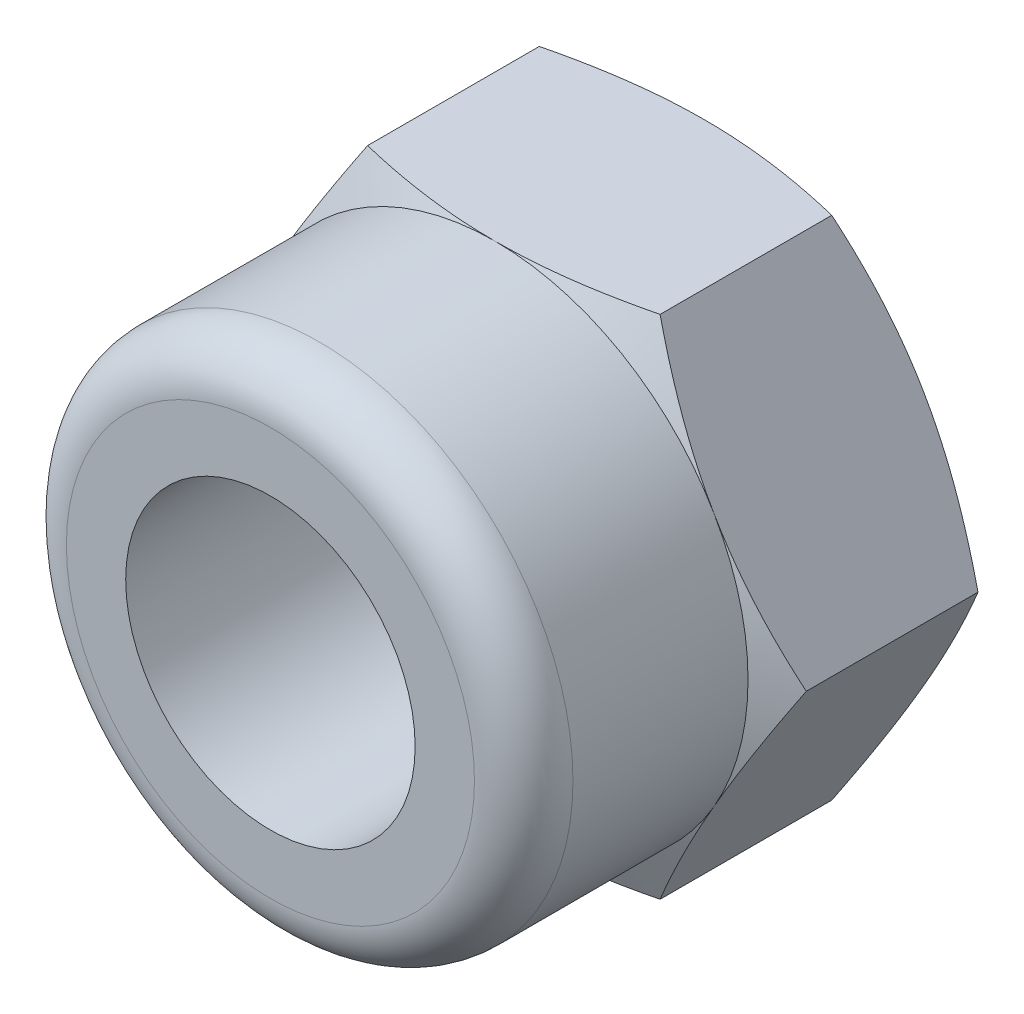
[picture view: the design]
ISO-10303-21;
HEADER;
FILE_DESCRIPTION(('STEP AP214'),'2;1');
FILE_NAME('part.step','',(''),(''),'','','');
FILE_SCHEMA(('AUTOMOTIVE_DESIGN { 1 0 10303 214 1 1 1 1 }'));
ENDSEC;
DATA;
#1=APPLICATION_CONTEXT('core data for automotive mechanical design processes');
#2=APPLICATION_PROTOCOL_DEFINITION('international standard','automotive_design',2000,#1);
#3=PRODUCT_CONTEXT('',#1,'mechanical');
#4=PRODUCT('Part','Part','',(#3));
#5=PRODUCT_RELATED_PRODUCT_CATEGORY('part','',(#4));
#6=PRODUCT_DEFINITION_FORMATION('','',#4);
#7=PRODUCT_DEFINITION_CONTEXT('part definition',#1,'design');
#8=PRODUCT_DEFINITION('design','',#6,#7);
#9=PRODUCT_DEFINITION_SHAPE('','',#8);
#10=(LENGTH_UNIT() NAMED_UNIT(*) SI_UNIT(.MILLI.,.METRE.));
#11=(NAMED_UNIT(*) PLANE_ANGLE_UNIT() SI_UNIT($,.RADIAN.));
#12=(NAMED_UNIT(*) SI_UNIT($,.STERADIAN.) SOLID_ANGLE_UNIT());
#13=UNCERTAINTY_MEASURE_WITH_UNIT(LENGTH_MEASURE(1.E-05),#10,'distance_accuracy_value','');
#14=(GEOMETRIC_REPRESENTATION_CONTEXT(3) GLOBAL_UNCERTAINTY_ASSIGNED_CONTEXT((#13)) GLOBAL_UNIT_ASSIGNED_CONTEXT((#10,
#11,#12)) REPRESENTATION_CONTEXT('',''));
#15=CARTESIAN_POINT('',(0.,0.,0.));
#16=DIRECTION('',(0.,0.,1.));
#17=DIRECTION('',(1.,0.,0.));
#18=AXIS2_PLACEMENT_3D('',#15,#16,#17);
#19=CARTESIAN_POINT('',(-4.04145188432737,0.,2.9));
#20=DIRECTION('',(0.86602540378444,-0.499999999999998,0.));
#21=DIRECTION('',(0.499999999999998,0.86602540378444,0.));
#22=AXIS2_PLACEMENT_3D('',#19,#20,#21);
#23=PLANE('',#22);
#24=CARTESIAN_POINT('',(-4.0415673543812,-0.000200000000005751,2.63630741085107));
#25=CARTESIAN_POINT('',(-3.9830643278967,0.101130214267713,2.66479349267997));
#26=CARTESIAN_POINT('',(-3.92433803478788,0.202847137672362,2.69153748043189));
#27=CARTESIAN_POINT('',(-3.80642809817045,0.407073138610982,2.74095110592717));
#28=CARTESIAN_POINT('',(-3.74724423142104,0.509582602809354,2.76361860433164));
#29=CARTESIAN_POINT('',(-3.62839363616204,0.715437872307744,2.80428400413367));
#30=CARTESIAN_POINT('',(-3.56872638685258,0.818784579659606,2.82227589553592));
#31=CARTESIAN_POINT('',(-3.44905985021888,1.02605310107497,2.85296825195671));
#32=CARTESIAN_POINT('',(-3.38906062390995,1.12997480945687,2.86566965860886));
#33=CARTESIAN_POINT('',(-3.27014272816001,1.33594664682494,2.88509966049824));
#34=CARTESIAN_POINT('',(-3.2112292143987,1.43798784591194,2.89195312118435));
#35=CARTESIAN_POINT('',(-3.09330061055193,1.64224617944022,2.89988573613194));
#36=CARTESIAN_POINT('',(-3.0342855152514,1.74446332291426,2.9009645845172));
#37=CARTESIAN_POINT('',(-2.91636155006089,1.9487136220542,2.89730537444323));
#38=CARTESIAN_POINT('',(-2.85745263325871,2.05074685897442,2.89257326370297));
#39=CARTESIAN_POINT('',(-2.73982177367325,2.25448948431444,2.8774903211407));
#40=CARTESIAN_POINT('',(-2.6810998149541,2.35619890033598,2.86713998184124));
#41=CARTESIAN_POINT('',(-2.5720716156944,2.54504128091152,2.84300281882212));
#42=CARTESIAN_POINT('',(-2.52172731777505,2.63224016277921,2.82989137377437));
#43=CARTESIAN_POINT('',(-2.42130191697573,2.80618205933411,2.80010631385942));
#44=CARTESIAN_POINT('',(-2.37122082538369,2.89292505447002,2.78343254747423));
#45=CARTESIAN_POINT('',(-2.27085880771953,3.06675716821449,2.74669891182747));
#46=CARTESIAN_POINT('',(-2.2205808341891,3.15384117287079,2.72660706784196));
#47=CARTESIAN_POINT('',(-2.12035232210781,3.32744204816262,2.6835328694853));
#48=CARTESIAN_POINT('',(-2.07040167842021,3.41395910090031,2.66055149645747));
#49=CARTESIAN_POINT('',(-2.02061047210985,3.50020000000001,2.63630741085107));
#50=B_SPLINE_CURVE_WITH_KNOTS('',3,(#24,#25,#26,#27,#28,#29,#30,#31,#32,#33,#34,#35,#36,#37,#38,
#39,#40,#41,#42,#43,#44,#45,#46,#47,#48,#49),.UNSPECIFIED.,.F.,.F.,(4,2,2,2,2,2,2,2,2,2,2,2,4),
(0.,0.361290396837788,0.722769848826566,1.08471167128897,1.44658904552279,1.80053110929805,
2.15449192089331,2.50809074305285,2.86165857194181,3.16620775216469,3.47076988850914,
3.77835581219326,4.08583755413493),.UNSPECIFIED.);
#51=CARTESIAN_POINT('',(-4.04145188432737,0.,2.63636363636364));
#52=VERTEX_POINT('',#51);
#53=CARTESIAN_POINT('',(-3.0310889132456,1.75000000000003,2.9));
#54=VERTEX_POINT('',#53);
#55=EDGE_CURVE('E142',#52,#54,#50,.T.);
#56=ORIENTED_EDGE('',*,*,#55,.T.);
#57=CARTESIAN_POINT('',(-2.02072594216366,3.5,2.63636363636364));
#58=VERTEX_POINT('',#57);
#59=EDGE_CURVE('E148',#54,#58,#50,.T.);
#60=ORIENTED_EDGE('',*,*,#59,.T.);
#61=DIRECTION('',(0.,0.,-1.));
#62=VECTOR('',#61,1.);
#63=CARTESIAN_POINT('',(-2.02072594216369,3.5,2.9));
#64=LINE('',#63,#62);
#65=CARTESIAN_POINT('',(-2.02072594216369,3.5,0.263636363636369));
#66=VERTEX_POINT('',#65);
#67=EDGE_CURVE('E232',#58,#66,#64,.T.);
#68=ORIENTED_EDGE('',*,*,#67,.T.);
#69=CARTESIAN_POINT('',(-2.02061047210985,3.50020000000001,0.263692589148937));
#70=CARTESIAN_POINT('',(-2.07911349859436,3.39886978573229,0.235206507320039));
#71=CARTESIAN_POINT('',(-2.13783979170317,3.29715286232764,0.20846251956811));
#72=CARTESIAN_POINT('',(-2.2557497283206,3.09292686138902,0.15904889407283));
#73=CARTESIAN_POINT('',(-2.31493359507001,2.99041739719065,0.136381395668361));
#74=CARTESIAN_POINT('',(-2.43378419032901,2.78456212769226,0.0957159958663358));
#75=CARTESIAN_POINT('',(-2.49345143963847,2.6812154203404,0.0777241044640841));
#76=CARTESIAN_POINT('',(-2.61311797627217,2.47394689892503,0.0470317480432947));
#77=CARTESIAN_POINT('',(-2.6731172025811,2.37002519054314,0.0343303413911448));
#78=CARTESIAN_POINT('',(-2.79203509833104,2.16405335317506,0.0149003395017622));
#79=CARTESIAN_POINT('',(-2.85094861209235,2.06201215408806,0.00804687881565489));
#80=CARTESIAN_POINT('',(-2.96887721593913,1.85775382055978,0.000114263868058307));
#81=CARTESIAN_POINT('',(-3.02789231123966,1.75553667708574,-0.000964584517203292));
#82=CARTESIAN_POINT('',(-3.14581627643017,1.5512863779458,0.00269462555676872));
#83=CARTESIAN_POINT('',(-3.20472519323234,1.44925314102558,0.00742673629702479));
#84=CARTESIAN_POINT('',(-3.3223560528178,1.24551051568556,0.0225096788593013));
#85=CARTESIAN_POINT('',(-3.38107801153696,1.14380109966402,0.0328600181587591));
#86=CARTESIAN_POINT('',(-3.49010621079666,0.954958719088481,0.0569971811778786));
#87=CARTESIAN_POINT('',(-3.540450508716,0.86775983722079,0.070108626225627));
#88=CARTESIAN_POINT('',(-3.64087590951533,0.693817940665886,0.0998936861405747));
#89=CARTESIAN_POINT('',(-3.69095700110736,0.607074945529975,0.11656745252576));
#90=CARTESIAN_POINT('',(-3.79131901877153,0.433242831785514,0.153301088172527));
#91=CARTESIAN_POINT('',(-3.84159699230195,0.346158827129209,0.17339293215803));
#92=CARTESIAN_POINT('',(-3.94182550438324,0.172557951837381,0.216467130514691));
#93=CARTESIAN_POINT('',(-3.99177614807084,0.0860408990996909,0.239448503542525));
#94=CARTESIAN_POINT('',(-4.0415673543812,-0.000200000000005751,0.263692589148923));
#95=B_SPLINE_CURVE_WITH_KNOTS('',3,(#69,#70,#71,#72,#73,#74,#75,#76,#77,#78,#79,#80,#81,#82,#83,
#84,#85,#86,#87,#88,#89,#90,#91,#92,#93,#94),.UNSPECIFIED.,.F.,.F.,(4,2,2,2,2,2,2,2,2,2,2,2,4),
(0.,0.361290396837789,0.722769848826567,1.08471167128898,1.44658904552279,1.80053110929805,
2.15449192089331,2.50809074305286,2.86165857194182,3.16620775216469,3.47076988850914,
3.77835581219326,4.08583755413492),.UNSPECIFIED.);
#96=CARTESIAN_POINT('',(-3.03108891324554,1.75,0.));
#97=VERTEX_POINT('',#96);
#98=EDGE_CURVE('E231',#66,#97,#95,.T.);
#99=ORIENTED_EDGE('',*,*,#98,.T.);
#100=CARTESIAN_POINT('',(-4.04145188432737,0.,0.263636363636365));
#101=VERTEX_POINT('',#100);
#102=EDGE_CURVE('E225',#97,#101,#95,.T.);
#103=ORIENTED_EDGE('',*,*,#102,.T.);
#104=DIRECTION('',(0.,0.,-1.));
#105=VECTOR('',#104,1.);
#106=CARTESIAN_POINT('',(-4.04145188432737,0.,2.9));
#107=LINE('',#106,#105);
#108=EDGE_CURVE('E241',#52,#101,#107,.T.);
#109=ORIENTED_EDGE('',*,*,#108,.F.);
#110=EDGE_LOOP('',(#56,#60,#68,#99,#103,#109));
#111=FACE_BOUND('',#110,.T.);
#112=ADVANCED_FACE('F31',(#111),#23,.F.);
#113=CARTESIAN_POINT('',(-2.02072594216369,-3.5,2.9));
#114=DIRECTION('',(0.86602540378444,0.499999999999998,0.));
#115=DIRECTION('',(-0.499999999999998,0.86602540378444,0.));
#116=AXIS2_PLACEMENT_3D('',#113,#114,#115);
#117=PLANE('',#116);
#118=CARTESIAN_POINT('',(-2.02061047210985,-3.50020000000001,2.63630741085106));
#119=CARTESIAN_POINT('',(-2.07911349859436,-3.39886978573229,2.66479349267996));
#120=CARTESIAN_POINT('',(-2.13783979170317,-3.29715286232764,2.69153748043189));
#121=CARTESIAN_POINT('',(-2.2557497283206,-3.09292686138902,2.74095110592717));
#122=CARTESIAN_POINT('',(-2.31493359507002,-2.99041739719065,2.76361860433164));
#123=CARTESIAN_POINT('',(-2.43378419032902,-2.78456212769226,2.80428400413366));
#124=CARTESIAN_POINT('',(-2.49345143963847,-2.6812154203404,2.82227589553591));
#125=CARTESIAN_POINT('',(-2.61311797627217,-2.47394689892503,2.8529682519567));
#126=CARTESIAN_POINT('',(-2.6731172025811,-2.37002519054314,2.86566965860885));
#127=CARTESIAN_POINT('',(-2.79203509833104,-2.16405335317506,2.88509966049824));
#128=CARTESIAN_POINT('',(-2.85094861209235,-2.06201215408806,2.89195312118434));
#129=CARTESIAN_POINT('',(-2.96887721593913,-1.85775382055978,2.89988573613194));
#130=CARTESIAN_POINT('',(-3.02789231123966,-1.75553667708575,2.9009645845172));
#131=CARTESIAN_POINT('',(-3.14581627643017,-1.5512863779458,2.89730537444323));
#132=CARTESIAN_POINT('',(-3.20472519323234,-1.44925314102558,2.89257326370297));
#133=CARTESIAN_POINT('',(-3.3223560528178,-1.24551051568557,2.8774903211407));
#134=CARTESIAN_POINT('',(-3.38107801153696,-1.14380109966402,2.86713998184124));
#135=CARTESIAN_POINT('',(-3.49010621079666,-0.954958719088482,2.84300281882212));
#136=CARTESIAN_POINT('',(-3.540450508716,-0.867759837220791,2.82989137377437));
#137=CARTESIAN_POINT('',(-3.64087590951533,-0.693817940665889,2.80010631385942));
#138=CARTESIAN_POINT('',(-3.69095700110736,-0.607074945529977,2.78343254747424));
#139=CARTESIAN_POINT('',(-3.79131901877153,-0.433242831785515,2.74669891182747));
#140=CARTESIAN_POINT('',(-3.84159699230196,-0.346158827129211,2.72660706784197));
#141=CARTESIAN_POINT('',(-3.94182550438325,-0.172557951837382,2.68353286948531));
#142=CARTESIAN_POINT('',(-3.99177614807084,-0.0860408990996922,2.66055149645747));
#143=CARTESIAN_POINT('',(-4.0415673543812,0.000200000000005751,2.63630741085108));
#144=B_SPLINE_CURVE_WITH_KNOTS('',3,(#118,#119,#120,#121,#122,#123,#124,#125,#126,#127,#128,
#129,#130,#131,#132,#133,#134,#135,#136,#137,#138,#139,#140,#141,#142,#143),.UNSPECIFIED.,.F.,
.F.,(4,2,2,2,2,2,2,2,2,2,2,2,4),(0.,0.361290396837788,0.722769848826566,1.08471167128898,
1.44658904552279,1.80053110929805,2.15449192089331,2.50809074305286,2.86165857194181,
3.16620775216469,3.47076988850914,3.77835581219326,4.08583755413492),.UNSPECIFIED.);
#145=CARTESIAN_POINT('',(-2.02072594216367,-3.5,2.63636363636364));
#146=VERTEX_POINT('',#145);
#147=CARTESIAN_POINT('',(-3.0310889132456,-1.75000000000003,2.9));
#148=VERTEX_POINT('',#147);
#149=EDGE_CURVE('E196',#146,#148,#144,.T.);
#150=ORIENTED_EDGE('',*,*,#149,.T.);
#151=EDGE_CURVE('E191',#148,#52,#144,.T.);
#152=ORIENTED_EDGE('',*,*,#151,.T.);
#153=ORIENTED_EDGE('',*,*,#108,.T.);
#154=CARTESIAN_POINT('',(-4.0415673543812,0.000200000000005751,0.26369258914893));
#155=CARTESIAN_POINT('',(-3.9830643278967,-0.101130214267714,0.235206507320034));
#156=CARTESIAN_POINT('',(-3.92433803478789,-0.202847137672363,0.208462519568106));
#157=CARTESIAN_POINT('',(-3.80642809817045,-0.407073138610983,0.159048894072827));
#158=CARTESIAN_POINT('',(-3.74724423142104,-0.509582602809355,0.136381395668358));
#159=CARTESIAN_POINT('',(-3.62839363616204,-0.715437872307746,0.0957159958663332));
#160=CARTESIAN_POINT('',(-3.56872638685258,-0.818784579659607,0.0777241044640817));
#161=CARTESIAN_POINT('',(-3.44905985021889,-1.02605310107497,0.0470317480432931));
#162=CARTESIAN_POINT('',(-3.38906062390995,-1.12997480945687,0.0343303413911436));
#163=CARTESIAN_POINT('',(-3.27014272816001,-1.33594664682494,0.014900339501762));
#164=CARTESIAN_POINT('',(-3.2112292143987,-1.43798784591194,0.00804687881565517));
#165=CARTESIAN_POINT('',(-3.09330061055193,-1.64224617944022,0.000114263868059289));
#166=CARTESIAN_POINT('',(-3.0342855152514,-1.74446332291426,-0.0009645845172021));
#167=CARTESIAN_POINT('',(-2.91636155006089,-1.94871362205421,0.00269462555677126));
#168=CARTESIAN_POINT('',(-2.85745263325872,-2.05074685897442,0.00742673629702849));
#169=CARTESIAN_POINT('',(-2.73982177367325,-2.25448948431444,0.0225096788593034));
#170=CARTESIAN_POINT('',(-2.6810998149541,-2.35619890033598,0.0328600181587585));
#171=CARTESIAN_POINT('',(-2.5720716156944,-2.54504128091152,0.0569971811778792));
#172=CARTESIAN_POINT('',(-2.52172731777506,-2.63224016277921,0.0701086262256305));
#173=CARTESIAN_POINT('',(-2.42130191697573,-2.80618205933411,0.0998936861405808));
#174=CARTESIAN_POINT('',(-2.3712208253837,-2.89292505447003,0.116567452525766));
#175=CARTESIAN_POINT('',(-2.27085880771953,-3.06675716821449,0.153301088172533));
#176=CARTESIAN_POINT('',(-2.2205808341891,-3.15384117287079,0.173392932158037));
#177=CARTESIAN_POINT('',(-2.12035232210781,-3.32744204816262,0.216467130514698));
#178=CARTESIAN_POINT('',(-2.07040167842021,-3.41395910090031,0.239448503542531));
#179=CARTESIAN_POINT('',(-2.02061047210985,-3.50020000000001,0.263692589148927));
#180=B_SPLINE_CURVE_WITH_KNOTS('',3,(#154,#155,#156,#157,#158,#159,#160,#161,#162,#163,#164,
#165,#166,#167,#168,#169,#170,#171,#172,#173,#174,#175,#176,#177,#178,#179),.UNSPECIFIED.,.F.,
.F.,(4,2,2,2,2,2,2,2,2,2,2,2,4),(0.,0.361290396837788,0.722769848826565,1.08471167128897,
1.44658904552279,1.80053110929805,2.15449192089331,2.50809074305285,2.86165857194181,
3.16620775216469,3.47076988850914,3.77835581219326,4.08583755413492),.UNSPECIFIED.);
#181=CARTESIAN_POINT('',(-3.03108891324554,-1.75,0.));
#182=VERTEX_POINT('',#181);
#183=EDGE_CURVE('E218',#101,#182,#180,.T.);
#184=ORIENTED_EDGE('',*,*,#183,.T.);
#185=CARTESIAN_POINT('',(-2.02072594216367,-3.5,0.263636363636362));
#186=VERTEX_POINT('',#185);
#187=EDGE_CURVE('E211',#182,#186,#180,.T.);
#188=ORIENTED_EDGE('',*,*,#187,.T.);
#189=DIRECTION('',(0.,0.,-1.));
#190=VECTOR('',#189,1.);
#191=CARTESIAN_POINT('',(-2.02072594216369,-3.5,2.9));
#192=LINE('',#191,#190);
#193=EDGE_CURVE('E239',#146,#186,#192,.T.);
#194=ORIENTED_EDGE('',*,*,#193,.F.);
#195=EDGE_LOOP('',(#150,#152,#153,#184,#188,#194));
#196=FACE_BOUND('',#195,.T.);
#197=ADVANCED_FACE('F203',(#196),#117,.F.);
#198=CARTESIAN_POINT('',(2.02072594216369,-3.5,2.9));
#199=DIRECTION('',(0.,1.,0.));
#200=DIRECTION('',(-1.,0.,0.));
#201=AXIS2_PLACEMENT_3D('',#198,#199,#200);
#202=PLANE('',#201);
#203=CARTESIAN_POINT('',(-5.35762833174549,-3.5,1.48819291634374));
#204=CARTESIAN_POINT('',(-5.20059963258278,-3.5,1.55218418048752));
#205=CARTESIAN_POINT('',(-5.04328482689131,-3.5,1.61548637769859));
#206=CARTESIAN_POINT('',(-4.72793006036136,-3.5,1.7403198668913));
#207=CARTESIAN_POINT('',(-4.5698900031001,-3.5,1.80185091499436));
#208=CARTESIAN_POINT('',(-4.25237985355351,-3.5,1.92295848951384));
#209=CARTESIAN_POINT('',(-4.09290662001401,-3.5,1.98252681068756));
#210=CARTESIAN_POINT('',(-3.77295921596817,-3.5,2.09890310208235));
#211=CARTESIAN_POINT('',(-3.61248508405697,-3.5,2.15571117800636));
#212=CARTESIAN_POINT('',(-3.2924883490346,-3.5,2.26511172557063));
#213=CARTESIAN_POINT('',(-3.13298159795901,-3.5,2.31775031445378));
#214=CARTESIAN_POINT('',(-2.81259704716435,-3.5,2.41873886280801));
#215=CARTESIAN_POINT('',(-2.65171916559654,-3.5,2.4670885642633));
#216=CARTESIAN_POINT('',(-2.32859419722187,-3.5,2.55829329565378));
#217=CARTESIAN_POINT('',(-2.16634889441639,-3.5,2.60115457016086));
#218=CARTESIAN_POINT('',(-1.84022495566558,-3.5,2.68003633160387));
#219=CARTESIAN_POINT('',(-1.67634659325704,-3.5,2.71605794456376));
#220=CARTESIAN_POINT('',(-1.29685540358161,-3.5,2.78930408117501));
#221=CARTESIAN_POINT('',(-1.08064332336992,-3.5,2.82357264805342));
#222=CARTESIAN_POINT('',(-0.754821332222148,-3.5,2.86157818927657));
#223=CARTESIAN_POINT('',(-0.645973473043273,-3.5,2.87201347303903));
#224=CARTESIAN_POINT('',(-0.427929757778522,-3.5,2.88811025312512));
#225=CARTESIAN_POINT('',(-0.318733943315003,-3.5,2.8937723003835));
#226=CARTESIAN_POINT('',(-0.0997480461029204,-3.5,2.90014238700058));
#227=CARTESIAN_POINT('',(0.0100426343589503,-3.5,2.90082996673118));
#228=CARTESIAN_POINT('',(0.229530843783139,-3.5,2.89717445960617));
#229=CARTESIAN_POINT('',(0.339228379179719,-3.5,2.89283175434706));
#230=CARTESIAN_POINT('',(0.558323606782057,-3.5,2.87926450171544));
#231=CARTESIAN_POINT('',(0.66772128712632,-3.5,2.87003976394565));
#232=CARTESIAN_POINT('',(0.886018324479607,-3.5,2.8470093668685));
#233=CARTESIAN_POINT('',(0.994917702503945,-3.5,2.83320390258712));
#234=CARTESIAN_POINT('',(1.410228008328,-3.5,2.77239198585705));
#235=CARTESIAN_POINT('',(1.71455266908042,-3.5,2.71076096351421));
#236=CARTESIAN_POINT('',(2.16667298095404,-3.5,2.60090160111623));
#237=CARTESIAN_POINT('',(2.31676453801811,-3.5,2.56134292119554));
#238=CARTESIAN_POINT('',(2.6156354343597,-3.5,2.47752008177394));
#239=CARTESIAN_POINT('',(2.76441486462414,-3.5,2.43325625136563));
#240=CARTESIAN_POINT('',(3.06177072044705,-3.5,2.34064523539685));
#241=CARTESIAN_POINT('',(3.21033917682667,-3.5,2.29227278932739));
#242=CARTESIAN_POINT('',(3.50644151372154,-3.5,2.19244905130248));
#243=CARTESIAN_POINT('',(3.65397535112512,-3.5,2.14099763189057));
#244=CARTESIAN_POINT('',(4.09507272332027,-3.5,1.98301836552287));
#245=CARTESIAN_POINT('',(4.38731421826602,-3.5,1.87280708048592));
#246=CARTESIAN_POINT('',(4.97163774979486,-3.5,1.64497921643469));
#247=CARTESIAN_POINT('',(5.26369865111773,-3.5,1.52730912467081));
#248=CARTESIAN_POINT('',(5.84599513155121,-3.5,1.28742842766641));
#249=CARTESIAN_POINT('',(6.13623042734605,-3.5,1.16521713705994));
#250=CARTESIAN_POINT('',(6.71091632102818,-3.5,0.919483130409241));
#251=CARTESIAN_POINT('',(6.99538767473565,-3.5,0.796008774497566));
#252=CARTESIAN_POINT('',(7.42130723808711,-3.5,0.609104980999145));
#253=CARTESIAN_POINT('',(7.56313135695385,-3.5,0.54652966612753));
#254=CARTESIAN_POINT('',(7.84655848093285,-3.5,0.420882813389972));
#255=CARTESIAN_POINT('',(7.98816148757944,-3.5,0.357811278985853));
#256=CARTESIAN_POINT('',(8.12966958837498,-3.5,0.294527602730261));
#257=B_SPLINE_CURVE_WITH_KNOTS('',3,(#203,#204,#205,#206,#207,#208,#209,#210,#211,#212,#213,
#214,#215,#216,#217,#218,#219,#220,#221,#222,#223,#224,#225,#226,#227,#228,#229,#230,#231,#232,
#233,#234,#235,#236,#237,#238,#239,#240,#241,#242,#243,#244,#245,#246,#247,#248,#249,#250,#251,
#252,#253,#254,#255,#256),.UNSPECIFIED.,.F.,.F.,(4,2,2,2,2,2,2,2,2,2,2,2,2,2,2,2,2,2,2,2,2,2,2,
2,2,2,4),(0.,0.508706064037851,1.01748184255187,1.52816774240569,2.03883407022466,
2.54268992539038,3.04657607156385,3.5498837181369,4.05310843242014,4.70913509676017,
5.03708789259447,5.36500283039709,5.69426569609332,6.0235035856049,6.35275431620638,
6.68199103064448,7.61182426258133,8.07745018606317,8.54304356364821,9.01174161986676,
9.48045909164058,10.4173206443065,11.361897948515,12.3066183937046,13.2369432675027,
13.7019885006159,14.1670304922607),.UNSPECIFIED.);
#258=CARTESIAN_POINT('',(2.0207259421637,-3.49999999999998,2.63636363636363));
#259=VERTEX_POINT('',#258);
#260=CARTESIAN_POINT('',(0.,-3.5,2.9));
#261=VERTEX_POINT('',#260);
#262=EDGE_CURVE('E288',#259,#261,#257,.F.);
#263=ORIENTED_EDGE('',*,*,#262,.T.);
#264=EDGE_CURVE('E197',#261,#146,#257,.F.);
#265=ORIENTED_EDGE('',*,*,#264,.T.);
#266=ORIENTED_EDGE('',*,*,#193,.T.);
#267=CARTESIAN_POINT('',(-5.35762833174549,-3.5,1.41180708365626));
#268=CARTESIAN_POINT('',(-5.20059963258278,-3.5,1.34781581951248));
#269=CARTESIAN_POINT('',(-5.04328482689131,-3.5,1.28451362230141));
#270=CARTESIAN_POINT('',(-4.72793006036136,-3.5,1.1596801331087));
#271=CARTESIAN_POINT('',(-4.5698900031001,-3.5,1.09814908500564));
#272=CARTESIAN_POINT('',(-4.25237985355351,-3.5,0.977041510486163));
#273=CARTESIAN_POINT('',(-4.09290662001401,-3.5,0.91747318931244));
#274=CARTESIAN_POINT('',(-3.77295921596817,-3.5,0.801096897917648));
#275=CARTESIAN_POINT('',(-3.61248508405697,-3.5,0.744288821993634));
#276=CARTESIAN_POINT('',(-3.2924883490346,-3.5,0.63488827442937));
#277=CARTESIAN_POINT('',(-3.13298159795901,-3.5,0.582249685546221));
#278=CARTESIAN_POINT('',(-2.81259704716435,-3.5,0.481261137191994));
#279=CARTESIAN_POINT('',(-2.65171916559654,-3.5,0.4329114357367));
#280=CARTESIAN_POINT('',(-2.32859419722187,-3.5,0.341706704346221));
#281=CARTESIAN_POINT('',(-2.16634889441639,-3.5,0.298845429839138));
#282=CARTESIAN_POINT('',(-1.84022495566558,-3.5,0.219963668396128));
#283=CARTESIAN_POINT('',(-1.67634659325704,-3.5,0.183942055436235));
#284=CARTESIAN_POINT('',(-1.29685540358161,-3.5,0.110695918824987));
#285=CARTESIAN_POINT('',(-1.08064332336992,-3.5,0.0764273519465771));
#286=CARTESIAN_POINT('',(-0.754821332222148,-3.5,0.0384218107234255));
#287=CARTESIAN_POINT('',(-0.645973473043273,-3.5,0.0279865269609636));
#288=CARTESIAN_POINT('',(-0.427929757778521,-3.5,0.0118897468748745));
#289=CARTESIAN_POINT('',(-0.318733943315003,-3.5,0.00622769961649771));
#290=CARTESIAN_POINT('',(-0.0997480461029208,-3.5,-0.000142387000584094));
#291=CARTESIAN_POINT('',(0.0100426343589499,-3.5,-0.000829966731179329));
#292=CARTESIAN_POINT('',(0.229530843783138,-3.5,0.0028255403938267));
#293=CARTESIAN_POINT('',(0.339228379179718,-3.5,0.00716824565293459));
#294=CARTESIAN_POINT('',(0.558323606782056,-3.5,0.0207354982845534));
#295=CARTESIAN_POINT('',(0.667721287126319,-3.5,0.029960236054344));
#296=CARTESIAN_POINT('',(0.886018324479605,-3.5,0.0529906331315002));
#297=CARTESIAN_POINT('',(0.994917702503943,-3.5,0.0667960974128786));
#298=CARTESIAN_POINT('',(1.410228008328,-3.5,0.127608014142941));
#299=CARTESIAN_POINT('',(1.71455266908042,-3.5,0.189239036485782));
#300=CARTESIAN_POINT('',(2.16667298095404,-3.5,0.299098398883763));
#301=CARTESIAN_POINT('',(2.31676453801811,-3.5,0.338657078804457));
#302=CARTESIAN_POINT('',(2.6156354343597,-3.5,0.422479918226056));
#303=CARTESIAN_POINT('',(2.76441486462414,-3.5,0.466743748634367));
#304=CARTESIAN_POINT('',(3.06177072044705,-3.5,0.559354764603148));
#305=CARTESIAN_POINT('',(3.21033917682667,-3.5,0.607727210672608));
#306=CARTESIAN_POINT('',(3.50644151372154,-3.5,0.707550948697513));
#307=CARTESIAN_POINT('',(3.65397535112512,-3.5,0.759002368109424));
#308=CARTESIAN_POINT('',(4.09507272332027,-3.5,0.916981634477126));
#309=CARTESIAN_POINT('',(4.38731421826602,-3.5,1.02719291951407));
#310=CARTESIAN_POINT('',(4.97163774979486,-3.5,1.2550207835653));
#311=CARTESIAN_POINT('',(5.26369865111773,-3.5,1.37269087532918));
#312=CARTESIAN_POINT('',(5.84599513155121,-3.5,1.61257157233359));
#313=CARTESIAN_POINT('',(6.13623042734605,-3.5,1.73478286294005));
#314=CARTESIAN_POINT('',(6.71091632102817,-3.5,1.98051686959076));
#315=CARTESIAN_POINT('',(6.99538767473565,-3.5,2.10399122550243));
#316=CARTESIAN_POINT('',(7.42130723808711,-3.5,2.29089501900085));
#317=CARTESIAN_POINT('',(7.56313135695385,-3.5,2.35347033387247));
#318=CARTESIAN_POINT('',(7.84655848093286,-3.5,2.47911718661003));
#319=CARTESIAN_POINT('',(7.98816148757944,-3.5,2.54218872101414));
#320=CARTESIAN_POINT('',(8.12966958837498,-3.5,2.60547239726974));
#321=B_SPLINE_CURVE_WITH_KNOTS('',3,(#267,#268,#269,#270,#271,#272,#273,#274,#275,#276,#277,
#278,#279,#280,#281,#282,#283,#284,#285,#286,#287,#288,#289,#290,#291,#292,#293,#294,#295,#296,
#297,#298,#299,#300,#301,#302,#303,#304,#305,#306,#307,#308,#309,#310,#311,#312,#313,#314,#315,
#316,#317,#318,#319,#320),.UNSPECIFIED.,.F.,.F.,(4,2,2,2,2,2,2,2,2,2,2,2,2,2,2,2,2,2,2,2,2,2,2,
2,2,2,4),(0.,0.508706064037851,1.01748184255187,1.52816774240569,2.03883407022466,
2.54268992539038,3.04657607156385,3.5498837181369,4.05310843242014,4.70913509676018,
5.03708789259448,5.36500283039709,5.69426569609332,6.0235035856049,6.35275431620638,
6.68199103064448,7.61182426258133,8.07745018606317,8.54304356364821,9.01174161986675,
9.48045909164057,10.4173206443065,11.361897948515,12.3066183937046,13.2369432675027,
13.7019885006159,14.1670304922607),.UNSPECIFIED.);
#322=CARTESIAN_POINT('',(0.,-3.5,0.));
#323=VERTEX_POINT('',#322);
#324=EDGE_CURVE('E219',#186,#323,#321,.T.);
#325=ORIENTED_EDGE('',*,*,#324,.T.);
#326=CARTESIAN_POINT('',(2.0207259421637,-3.49999999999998,0.263636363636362));
#327=VERTEX_POINT('',#326);
#328=EDGE_CURVE('E220',#323,#327,#321,.T.);
#329=ORIENTED_EDGE('',*,*,#328,.T.);
#330=DIRECTION('',(0.,0.,-1.));
#331=VECTOR('',#330,1.);
#332=CARTESIAN_POINT('',(2.02072594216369,-3.5,2.9));
#333=LINE('',#332,#331);
#334=EDGE_CURVE('E237',#259,#327,#333,.T.);
#335=ORIENTED_EDGE('',*,*,#334,.F.);
#336=EDGE_LOOP('',(#263,#265,#266,#325,#329,#335));
#337=FACE_BOUND('',#336,.T.);
#338=ADVANCED_FACE('F206',(#337),#202,.F.);
#339=CARTESIAN_POINT('',(4.04145188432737,0.,2.9));
#340=DIRECTION('',(-0.86602540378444,0.499999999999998,0.));
#341=DIRECTION('',(-0.499999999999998,-0.86602540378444,0.));
#342=AXIS2_PLACEMENT_3D('',#339,#340,#341);
#343=PLANE('',#342);
#344=CARTESIAN_POINT('',(4.0415673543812,0.000200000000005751,2.63630741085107));
#345=CARTESIAN_POINT('',(3.9830643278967,-0.101130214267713,2.66479349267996));
#346=CARTESIAN_POINT('',(3.92433803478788,-0.202847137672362,2.69153748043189));
#347=CARTESIAN_POINT('',(3.80642809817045,-0.407073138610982,2.74095110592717));
#348=CARTESIAN_POINT('',(3.74724423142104,-0.509582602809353,2.76361860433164));
#349=CARTESIAN_POINT('',(3.62839363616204,-0.715437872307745,2.80428400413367));
#350=CARTESIAN_POINT('',(3.56872638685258,-0.818784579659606,2.82227589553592));
#351=CARTESIAN_POINT('',(3.44905985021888,-1.02605310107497,2.85296825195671));
#352=CARTESIAN_POINT('',(3.38906062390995,-1.12997480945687,2.86566965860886));
#353=CARTESIAN_POINT('',(3.27014272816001,-1.33594664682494,2.88509966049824));
#354=CARTESIAN_POINT('',(3.2112292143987,-1.43798784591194,2.89195312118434));
#355=CARTESIAN_POINT('',(3.09330061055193,-1.64224617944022,2.89988573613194));
#356=CARTESIAN_POINT('',(3.0342855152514,-1.74446332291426,2.9009645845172));
#357=CARTESIAN_POINT('',(2.91636155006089,-1.9487136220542,2.89730537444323));
#358=CARTESIAN_POINT('',(2.85745263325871,-2.05074685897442,2.89257326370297));
#359=CARTESIAN_POINT('',(2.73982177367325,-2.25448948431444,2.8774903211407));
#360=CARTESIAN_POINT('',(2.6810998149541,-2.35619890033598,2.86713998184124));
#361=CARTESIAN_POINT('',(2.5720716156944,-2.54504128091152,2.84300281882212));
#362=CARTESIAN_POINT('',(2.52172731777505,-2.63224016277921,2.82989137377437));
#363=CARTESIAN_POINT('',(2.42130191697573,-2.80618205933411,2.80010631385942));
#364=CARTESIAN_POINT('',(2.37122082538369,-2.89292505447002,2.78343254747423));
#365=CARTESIAN_POINT('',(2.27085880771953,-3.06675716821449,2.74669891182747));
#366=CARTESIAN_POINT('',(2.2205808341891,-3.15384117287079,2.72660706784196));
#367=CARTESIAN_POINT('',(2.12035232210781,-3.32744204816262,2.6835328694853));
#368=CARTESIAN_POINT('',(2.07040167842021,-3.41395910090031,2.66055149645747));
#369=CARTESIAN_POINT('',(2.02061047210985,-3.50020000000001,2.63630741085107));
#370=B_SPLINE_CURVE_WITH_KNOTS('',3,(#344,#345,#346,#347,#348,#349,#350,#351,#352,#353,#354,
#355,#356,#357,#358,#359,#360,#361,#362,#363,#364,#365,#366,#367,#368,#369),.UNSPECIFIED.,.F.,
.F.,(4,2,2,2,2,2,2,2,2,2,2,2,4),(0.,0.361290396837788,0.722769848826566,1.08471167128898,
1.44658904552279,1.80053110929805,2.15449192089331,2.50809074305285,2.86165857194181,
3.16620775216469,3.47076988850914,3.77835581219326,4.08583755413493),.UNSPECIFIED.);
#371=CARTESIAN_POINT('',(4.04145188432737,0.,2.63636363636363));
#372=VERTEX_POINT('',#371);
#373=CARTESIAN_POINT('',(3.03108891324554,-1.75,2.9));
#374=VERTEX_POINT('',#373);
#375=EDGE_CURVE('E139',#372,#374,#370,.T.);
#376=ORIENTED_EDGE('',*,*,#375,.T.);
#377=EDGE_CURVE('E289',#374,#259,#370,.T.);
#378=ORIENTED_EDGE('',*,*,#377,.T.);
#379=ORIENTED_EDGE('',*,*,#334,.T.);
#380=CARTESIAN_POINT('',(2.02061047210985,-3.50020000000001,0.263692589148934));
#381=CARTESIAN_POINT('',(2.07911349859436,-3.39886978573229,0.235206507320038));
#382=CARTESIAN_POINT('',(2.13783979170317,-3.29715286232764,0.20846251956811));
#383=CARTESIAN_POINT('',(2.2557497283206,-3.09292686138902,0.15904889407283));
#384=CARTESIAN_POINT('',(2.31493359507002,-2.99041739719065,0.136381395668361));
#385=CARTESIAN_POINT('',(2.43378419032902,-2.78456212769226,0.0957159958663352));
#386=CARTESIAN_POINT('',(2.49345143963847,-2.68121542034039,0.0777241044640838));
#387=CARTESIAN_POINT('',(2.61311797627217,-2.47394689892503,0.0470317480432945));
#388=CARTESIAN_POINT('',(2.6731172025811,-2.37002519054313,0.0343303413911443));
#389=CARTESIAN_POINT('',(2.79203509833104,-2.16405335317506,0.0149003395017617));
#390=CARTESIAN_POINT('',(2.85094861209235,-2.06201215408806,0.00804687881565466));
#391=CARTESIAN_POINT('',(2.96887721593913,-1.85775382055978,0.000114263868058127));
#392=CARTESIAN_POINT('',(3.02789231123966,-1.75553667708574,-0.000964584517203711));
#393=CARTESIAN_POINT('',(3.14581627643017,-1.5512863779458,0.00269462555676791));
#394=CARTESIAN_POINT('',(3.20472519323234,-1.44925314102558,0.00742673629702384));
#395=CARTESIAN_POINT('',(3.3223560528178,-1.24551051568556,0.0225096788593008));
#396=CARTESIAN_POINT('',(3.38107801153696,-1.14380109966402,0.0328600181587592));
#397=CARTESIAN_POINT('',(3.49010621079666,-0.954958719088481,0.0569971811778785));
#398=CARTESIAN_POINT('',(3.540450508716,-0.86775983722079,0.0701086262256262));
#399=CARTESIAN_POINT('',(3.64087590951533,-0.693817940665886,0.0998936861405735));
#400=CARTESIAN_POINT('',(3.69095700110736,-0.607074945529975,0.116567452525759));
#401=CARTESIAN_POINT('',(3.79131901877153,-0.433242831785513,0.153301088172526));
#402=CARTESIAN_POINT('',(3.84159699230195,-0.346158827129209,0.173392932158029));
#403=CARTESIAN_POINT('',(3.94182550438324,-0.172557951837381,0.21646713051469));
#404=CARTESIAN_POINT('',(3.99177614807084,-0.0860408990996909,0.239448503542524));
#405=CARTESIAN_POINT('',(4.0415673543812,0.000200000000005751,0.263692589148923));
#406=B_SPLINE_CURVE_WITH_KNOTS('',3,(#380,#381,#382,#383,#384,#385,#386,#387,#388,#389,#390,
#391,#392,#393,#394,#395,#396,#397,#398,#399,#400,#401,#402,#403,#404,#405),.UNSPECIFIED.,.F.,
.F.,(4,2,2,2,2,2,2,2,2,2,2,2,4),(0.,0.361290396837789,0.722769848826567,1.08471167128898,
1.44658904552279,1.80053110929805,2.15449192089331,2.50809074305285,2.86165857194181,
3.16620775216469,3.47076988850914,3.77835581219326,4.08583755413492),.UNSPECIFIED.);
#407=CARTESIAN_POINT('',(3.03108891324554,-1.75,0.));
#408=VERTEX_POINT('',#407);
#409=EDGE_CURVE('E306',#327,#408,#406,.T.);
#410=ORIENTED_EDGE('',*,*,#409,.T.);
#411=CARTESIAN_POINT('',(4.04145188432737,0.,0.263636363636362));
#412=VERTEX_POINT('',#411);
#413=EDGE_CURVE('E296',#408,#412,#406,.T.);
#414=ORIENTED_EDGE('',*,*,#413,.T.);
#415=DIRECTION('',(0.,0.,-1.));
#416=VECTOR('',#415,1.);
#417=CARTESIAN_POINT('',(4.04145188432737,0.,2.9));
#418=LINE('',#417,#416);
#419=EDGE_CURVE('E235',#372,#412,#418,.T.);
#420=ORIENTED_EDGE('',*,*,#419,.F.);
#421=EDGE_LOOP('',(#376,#378,#379,#410,#414,#420));
#422=FACE_BOUND('',#421,.T.);
#423=ADVANCED_FACE('F293',(#422),#343,.F.);
#424=CARTESIAN_POINT('',(2.02072594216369,3.5,2.9));
#425=DIRECTION('',(-0.86602540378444,-0.499999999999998,0.));
#426=DIRECTION('',(0.499999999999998,-0.86602540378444,0.));
#427=AXIS2_PLACEMENT_3D('',#424,#425,#426);
#428=PLANE('',#427);
#429=CARTESIAN_POINT('',(2.02061047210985,3.50020000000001,2.63630741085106));
#430=CARTESIAN_POINT('',(2.07911349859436,3.39886978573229,2.66479349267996));
#431=CARTESIAN_POINT('',(2.13783979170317,3.29715286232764,2.69153748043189));
#432=CARTESIAN_POINT('',(2.2557497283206,3.09292686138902,2.74095110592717));
#433=CARTESIAN_POINT('',(2.31493359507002,2.99041739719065,2.76361860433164));
#434=CARTESIAN_POINT('',(2.43378419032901,2.78456212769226,2.80428400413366));
#435=CARTESIAN_POINT('',(2.49345143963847,2.6812154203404,2.82227589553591));
#436=CARTESIAN_POINT('',(2.61311797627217,2.47394689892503,2.8529682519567));
#437=CARTESIAN_POINT('',(2.6731172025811,2.37002519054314,2.86566965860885));
#438=CARTESIAN_POINT('',(2.79203509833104,2.16405335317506,2.88509966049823));
#439=CARTESIAN_POINT('',(2.85094861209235,2.06201215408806,2.89195312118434));
#440=CARTESIAN_POINT('',(2.96887721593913,1.85775382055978,2.89988573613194));
#441=CARTESIAN_POINT('',(3.02789231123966,1.75553667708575,2.9009645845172));
#442=CARTESIAN_POINT('',(3.14581627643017,1.5512863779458,2.89730537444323));
#443=CARTESIAN_POINT('',(3.20472519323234,1.44925314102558,2.89257326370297));
#444=CARTESIAN_POINT('',(3.3223560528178,1.24551051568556,2.8774903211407));
#445=CARTESIAN_POINT('',(3.38107801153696,1.14380109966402,2.86713998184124));
#446=CARTESIAN_POINT('',(3.49010621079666,0.954958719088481,2.84300281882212));
#447=CARTESIAN_POINT('',(3.540450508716,0.867759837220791,2.82989137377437));
#448=CARTESIAN_POINT('',(3.64087590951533,0.693817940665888,2.80010631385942));
#449=CARTESIAN_POINT('',(3.69095700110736,0.607074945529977,2.78343254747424));
#450=CARTESIAN_POINT('',(3.79131901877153,0.433242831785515,2.74669891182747));
#451=CARTESIAN_POINT('',(3.84159699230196,0.346158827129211,2.72660706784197));
#452=CARTESIAN_POINT('',(3.94182550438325,0.172557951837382,2.68353286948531));
#453=CARTESIAN_POINT('',(3.99177614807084,0.0860408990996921,2.66055149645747));
#454=CARTESIAN_POINT('',(4.0415673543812,-0.000200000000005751,2.63630741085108));
#455=B_SPLINE_CURVE_WITH_KNOTS('',3,(#429,#430,#431,#432,#433,#434,#435,#436,#437,#438,#439,
#440,#441,#442,#443,#444,#445,#446,#447,#448,#449,#450,#451,#452,#453,#454),.UNSPECIFIED.,.F.,
.F.,(4,2,2,2,2,2,2,2,2,2,2,2,4),(0.,0.361290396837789,0.722769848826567,1.08471167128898,
1.44658904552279,1.80053110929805,2.15449192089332,2.50809074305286,2.86165857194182,
3.16620775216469,3.47076988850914,3.77835581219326,4.08583755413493),.UNSPECIFIED.);
#456=CARTESIAN_POINT('',(2.02072594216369,3.5,2.63636363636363));
#457=VERTEX_POINT('',#456);
#458=CARTESIAN_POINT('',(3.03108891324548,1.74999999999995,2.9));
#459=VERTEX_POINT('',#458);
#460=EDGE_CURVE('E46',#457,#459,#455,.T.);
#461=ORIENTED_EDGE('',*,*,#460,.T.);
#462=EDGE_CURVE('E137',#459,#372,#455,.T.);
#463=ORIENTED_EDGE('',*,*,#462,.T.);
#464=ORIENTED_EDGE('',*,*,#419,.T.);
#465=CARTESIAN_POINT('',(4.0415673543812,-0.000200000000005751,0.26369258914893));
#466=CARTESIAN_POINT('',(3.9830643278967,0.101130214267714,0.235206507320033));
#467=CARTESIAN_POINT('',(3.92433803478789,0.202847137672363,0.208462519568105));
#468=CARTESIAN_POINT('',(3.80642809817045,0.407073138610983,0.159048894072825));
#469=CARTESIAN_POINT('',(3.74724423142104,0.509582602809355,0.136381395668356));
#470=CARTESIAN_POINT('',(3.62839363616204,0.715437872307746,0.0957159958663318));
#471=CARTESIAN_POINT('',(3.56872638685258,0.818784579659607,0.0777241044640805));
#472=CARTESIAN_POINT('',(3.44905985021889,1.02605310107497,0.0470317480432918));
#473=CARTESIAN_POINT('',(3.38906062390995,1.12997480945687,0.0343303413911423));
#474=CARTESIAN_POINT('',(3.27014272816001,1.33594664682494,0.0149003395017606));
#475=CARTESIAN_POINT('',(3.2112292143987,1.43798784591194,0.00804687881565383));
#476=CARTESIAN_POINT('',(3.09330061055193,1.64224617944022,0.00011426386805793));
#477=CARTESIAN_POINT('',(3.0342855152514,1.74446332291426,-0.000964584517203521));
#478=CARTESIAN_POINT('',(2.91636155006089,1.9487136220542,0.00269462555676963));
#479=CARTESIAN_POINT('',(2.85745263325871,2.05074685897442,0.00742673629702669));
#480=CARTESIAN_POINT('',(2.73982177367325,2.25448948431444,0.0225096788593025));
#481=CARTESIAN_POINT('',(2.6810998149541,2.35619890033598,0.0328600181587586));
#482=CARTESIAN_POINT('',(2.5720716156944,2.54504128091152,0.0569971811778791));
#483=CARTESIAN_POINT('',(2.52172731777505,2.63224016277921,0.0701086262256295));
#484=CARTESIAN_POINT('',(2.42130191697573,2.80618205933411,0.0998936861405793));
#485=CARTESIAN_POINT('',(2.37122082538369,2.89292505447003,0.116567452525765));
#486=CARTESIAN_POINT('',(2.27085880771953,3.06675716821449,0.153301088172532));
#487=CARTESIAN_POINT('',(2.2205808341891,3.15384117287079,0.173392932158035));
#488=CARTESIAN_POINT('',(2.12035232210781,3.32744204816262,0.216467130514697));
#489=CARTESIAN_POINT('',(2.07040167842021,3.41395910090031,0.239448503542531));
#490=CARTESIAN_POINT('',(2.02061047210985,3.50020000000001,0.26369258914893));
#491=B_SPLINE_CURVE_WITH_KNOTS('',3,(#465,#466,#467,#468,#469,#470,#471,#472,#473,#474,#475,
#476,#477,#478,#479,#480,#481,#482,#483,#484,#485,#486,#487,#488,#489,#490),.UNSPECIFIED.,.F.,
.F.,(4,2,2,2,2,2,2,2,2,2,2,2,4),(0.,0.361290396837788,0.722769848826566,1.08471167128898,
1.44658904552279,1.80053110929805,2.15449192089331,2.50809074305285,2.86165857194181,
3.16620775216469,3.47076988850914,3.77835581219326,4.08583755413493),.UNSPECIFIED.);
#492=CARTESIAN_POINT('',(3.03108891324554,1.75,0.));
#493=VERTEX_POINT('',#492);
#494=EDGE_CURVE('E299',#412,#493,#491,.T.);
#495=ORIENTED_EDGE('',*,*,#494,.T.);
#496=CARTESIAN_POINT('',(2.02072594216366,3.5,0.263636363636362));
#497=VERTEX_POINT('',#496);
#498=EDGE_CURVE('E304',#493,#497,#491,.T.);
#499=ORIENTED_EDGE('',*,*,#498,.T.);
#500=DIRECTION('',(0.,0.,-1.));
#501=VECTOR('',#500,1.);
#502=CARTESIAN_POINT('',(2.02072594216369,3.5,2.9));
#503=LINE('',#502,#501);
#504=EDGE_CURVE('E147',#457,#497,#503,.T.);
#505=ORIENTED_EDGE('',*,*,#504,.F.);
#506=EDGE_LOOP('',(#461,#463,#464,#495,#499,#505));
#507=FACE_BOUND('',#506,.T.);
#508=ADVANCED_FACE('F145',(#507),#428,.F.);
#509=CARTESIAN_POINT('',(-2.02072594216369,3.5,2.9));
#510=DIRECTION('',(0.,-1.,0.));
#511=DIRECTION('',(1.,0.,0.));
#512=AXIS2_PLACEMENT_3D('',#509,#510,#511);
#513=PLANE('',#512);
#514=CARTESIAN_POINT('',(-5.35762833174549,3.5,1.48819291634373));
#515=CARTESIAN_POINT('',(-5.20059963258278,3.5,1.55218418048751));
#516=CARTESIAN_POINT('',(-5.04328482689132,3.5,1.61548637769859));
#517=CARTESIAN_POINT('',(-4.72793006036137,3.5,1.7403198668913));
#518=CARTESIAN_POINT('',(-4.56989000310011,3.5,1.80185091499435));
#519=CARTESIAN_POINT('',(-4.25237985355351,3.5,1.92295848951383));
#520=CARTESIAN_POINT('',(-4.09290662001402,3.5,1.98252681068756));
#521=CARTESIAN_POINT('',(-3.77295921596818,3.5,2.09890310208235));
#522=CARTESIAN_POINT('',(-3.61248508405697,3.5,2.15571117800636));
#523=CARTESIAN_POINT('',(-3.29248834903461,3.5,2.26511172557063));
#524=CARTESIAN_POINT('',(-3.13298159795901,3.5,2.31775031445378));
#525=CARTESIAN_POINT('',(-2.81259704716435,3.5,2.41873886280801));
#526=CARTESIAN_POINT('',(-2.65171916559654,3.5,2.4670885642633));
#527=CARTESIAN_POINT('',(-2.32859419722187,3.5,2.55829329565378));
#528=CARTESIAN_POINT('',(-2.16634889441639,3.5,2.60115457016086));
#529=CARTESIAN_POINT('',(-1.84022495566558,3.5,2.68003633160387));
#530=CARTESIAN_POINT('',(-1.67634659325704,3.5,2.71605794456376));
#531=CARTESIAN_POINT('',(-1.29685540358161,3.5,2.78930408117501));
#532=CARTESIAN_POINT('',(-1.08064332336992,3.5,2.82357264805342));
#533=CARTESIAN_POINT('',(-0.754821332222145,3.5,2.86157818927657));
#534=CARTESIAN_POINT('',(-0.64597347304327,3.5,2.87201347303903));
#535=CARTESIAN_POINT('',(-0.427929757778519,3.5,2.88811025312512));
#536=CARTESIAN_POINT('',(-0.318733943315,3.5,2.8937723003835));
#537=CARTESIAN_POINT('',(-0.0997480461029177,3.5,2.90014238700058));
#538=CARTESIAN_POINT('',(0.010042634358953,3.5,2.90082996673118));
#539=CARTESIAN_POINT('',(0.229530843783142,3.5,2.89717445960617));
#540=CARTESIAN_POINT('',(0.339228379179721,3.5,2.89283175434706));
#541=CARTESIAN_POINT('',(0.558323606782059,3.5,2.87926450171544));
#542=CARTESIAN_POINT('',(0.667721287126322,3.5,2.87003976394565));
#543=CARTESIAN_POINT('',(0.886018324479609,3.5,2.8470093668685));
#544=CARTESIAN_POINT('',(0.994917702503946,3.5,2.83320390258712));
#545=CARTESIAN_POINT('',(1.410228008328,3.5,2.77239198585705));
#546=CARTESIAN_POINT('',(1.71455266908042,3.5,2.71076096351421));
#547=CARTESIAN_POINT('',(2.16667298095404,3.50000000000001,2.60090160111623));
#548=CARTESIAN_POINT('',(2.31676453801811,3.5,2.56134292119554));
#549=CARTESIAN_POINT('',(2.61563543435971,3.5,2.47752008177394));
#550=CARTESIAN_POINT('',(2.76441486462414,3.50000000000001,2.43325625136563));
#551=CARTESIAN_POINT('',(3.06177072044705,3.50000000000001,2.34064523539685));
#552=CARTESIAN_POINT('',(3.21033917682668,3.50000000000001,2.29227278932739));
#553=CARTESIAN_POINT('',(3.50644151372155,3.50000000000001,2.19244905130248));
#554=CARTESIAN_POINT('',(3.65397535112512,3.50000000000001,2.14099763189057));
#555=CARTESIAN_POINT('',(4.09507272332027,3.50000000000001,1.98301836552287));
#556=CARTESIAN_POINT('',(4.38731421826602,3.50000000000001,1.87280708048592));
#557=CARTESIAN_POINT('',(4.97163774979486,3.50000000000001,1.64497921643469));
#558=CARTESIAN_POINT('',(5.26369865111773,3.50000000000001,1.52730912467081));
#559=CARTESIAN_POINT('',(5.84599513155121,3.50000000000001,1.28742842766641));
#560=CARTESIAN_POINT('',(6.13623042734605,3.50000000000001,1.16521713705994));
#561=CARTESIAN_POINT('',(6.71091632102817,3.50000000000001,0.919483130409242));
#562=CARTESIAN_POINT('',(6.99538767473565,3.50000000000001,0.796008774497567));
#563=CARTESIAN_POINT('',(7.4213072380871,3.50000000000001,0.609104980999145));
#564=CARTESIAN_POINT('',(7.56313135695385,3.50000000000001,0.54652966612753));
#565=CARTESIAN_POINT('',(7.84655848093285,3.50000000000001,0.420882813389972));
#566=CARTESIAN_POINT('',(7.98816148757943,3.50000000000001,0.357811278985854));
#567=CARTESIAN_POINT('',(8.12966958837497,3.5,0.294527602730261));
#568=B_SPLINE_CURVE_WITH_KNOTS('',3,(#514,#515,#516,#517,#518,#519,#520,#521,#522,#523,#524,
#525,#526,#527,#528,#529,#530,#531,#532,#533,#534,#535,#536,#537,#538,#539,#540,#541,#542,#543,
#544,#545,#546,#547,#548,#549,#550,#551,#552,#553,#554,#555,#556,#557,#558,#559,#560,#561,#562,
#563,#564,#565,#566,#567),.UNSPECIFIED.,.F.,.F.,(4,2,2,2,2,2,2,2,2,2,2,2,2,2,2,2,2,2,2,2,2,2,2,
2,2,2,4),(0.,0.508706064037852,1.01748184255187,1.52816774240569,2.03883407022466,
2.54268992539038,3.04657607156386,3.54988371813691,4.05310843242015,4.70913509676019,
5.03708789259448,5.3650028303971,5.69426569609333,6.02350358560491,6.35275431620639,
6.68199103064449,7.61182426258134,8.07745018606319,8.54304356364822,9.01174161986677,
9.48045909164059,10.4173206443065,11.3618979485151,12.3066183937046,13.2369432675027,
13.7019885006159,14.1670304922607),.UNSPECIFIED.);
#569=CARTESIAN_POINT('',(0.,3.5,2.9));
#570=VERTEX_POINT('',#569);
#571=EDGE_CURVE('E149',#58,#570,#568,.T.);
#572=ORIENTED_EDGE('',*,*,#571,.T.);
#573=EDGE_CURVE('E133',#570,#457,#568,.T.);
#574=ORIENTED_EDGE('',*,*,#573,.T.);
#575=ORIENTED_EDGE('',*,*,#504,.T.);
#576=CARTESIAN_POINT('',(-5.35762833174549,3.5,1.41180708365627));
#577=CARTESIAN_POINT('',(-5.20059963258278,3.5,1.34781581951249));
#578=CARTESIAN_POINT('',(-5.04328482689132,3.5,1.28451362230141));
#579=CARTESIAN_POINT('',(-4.72793006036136,3.5,1.1596801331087));
#580=CARTESIAN_POINT('',(-4.5698900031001,3.5,1.09814908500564));
#581=CARTESIAN_POINT('',(-4.25237985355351,3.5,0.977041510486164));
#582=CARTESIAN_POINT('',(-4.09290662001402,3.5,0.91747318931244));
#583=CARTESIAN_POINT('',(-3.77295921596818,3.5,0.801096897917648));
#584=CARTESIAN_POINT('',(-3.61248508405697,3.5,0.744288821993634));
#585=CARTESIAN_POINT('',(-3.2924883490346,3.5,0.63488827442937));
#586=CARTESIAN_POINT('',(-3.13298159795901,3.5,0.582249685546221));
#587=CARTESIAN_POINT('',(-2.81259704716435,3.5,0.481261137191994));
#588=CARTESIAN_POINT('',(-2.65171916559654,3.5,0.4329114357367));
#589=CARTESIAN_POINT('',(-2.32859419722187,3.5,0.34170670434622));
#590=CARTESIAN_POINT('',(-2.16634889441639,3.5,0.298845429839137));
#591=CARTESIAN_POINT('',(-1.84022495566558,3.5,0.219963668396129));
#592=CARTESIAN_POINT('',(-1.67634659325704,3.5,0.183942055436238));
#593=CARTESIAN_POINT('',(-1.29685540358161,3.5,0.110695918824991));
#594=CARTESIAN_POINT('',(-1.08064332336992,3.5,0.0764273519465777));
#595=CARTESIAN_POINT('',(-0.754821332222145,3.5,0.038421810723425));
#596=CARTESIAN_POINT('',(-0.64597347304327,3.5,0.0279865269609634));
#597=CARTESIAN_POINT('',(-0.427929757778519,3.5,0.0118897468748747));
#598=CARTESIAN_POINT('',(-0.318733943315,3.5,0.0062276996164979));
#599=CARTESIAN_POINT('',(-0.0997480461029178,3.5,-0.000142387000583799));
#600=CARTESIAN_POINT('',(0.0100426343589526,3.5,-0.000829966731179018));
#601=CARTESIAN_POINT('',(0.229530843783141,3.5,0.00282554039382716));
#602=CARTESIAN_POINT('',(0.339228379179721,3.5,0.00716824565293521));
#603=CARTESIAN_POINT('',(0.558323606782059,3.5,0.020735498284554));
#604=CARTESIAN_POINT('',(0.667721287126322,3.5,0.0299602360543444));
#605=CARTESIAN_POINT('',(0.886018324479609,3.5,0.0529906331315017));
#606=CARTESIAN_POINT('',(0.994917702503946,3.5,0.0667960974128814));
#607=CARTESIAN_POINT('',(1.410228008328,3.5,0.127608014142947));
#608=CARTESIAN_POINT('',(1.71455266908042,3.5,0.189239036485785));
#609=CARTESIAN_POINT('',(2.16667298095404,3.50000000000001,0.299098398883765));
#610=CARTESIAN_POINT('',(2.31676453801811,3.5,0.338657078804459));
#611=CARTESIAN_POINT('',(2.61563543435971,3.5,0.422479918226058));
#612=CARTESIAN_POINT('',(2.76441486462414,3.50000000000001,0.466743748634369));
#613=CARTESIAN_POINT('',(3.06177072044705,3.50000000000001,0.55935476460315));
#614=CARTESIAN_POINT('',(3.21033917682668,3.50000000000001,0.60772721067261));
#615=CARTESIAN_POINT('',(3.50644151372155,3.50000000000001,0.707550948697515));
#616=CARTESIAN_POINT('',(3.65397535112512,3.50000000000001,0.759002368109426));
#617=CARTESIAN_POINT('',(4.09507272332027,3.50000000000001,0.916981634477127));
#618=CARTESIAN_POINT('',(4.38731421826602,3.50000000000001,1.02719291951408));
#619=CARTESIAN_POINT('',(4.97163774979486,3.50000000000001,1.25502078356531));
#620=CARTESIAN_POINT('',(5.26369865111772,3.50000000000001,1.37269087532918));
#621=CARTESIAN_POINT('',(5.84599513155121,3.50000000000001,1.61257157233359));
#622=CARTESIAN_POINT('',(6.13623042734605,3.50000000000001,1.73478286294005));
#623=CARTESIAN_POINT('',(6.71091632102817,3.50000000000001,1.98051686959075));
#624=CARTESIAN_POINT('',(6.99538767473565,3.50000000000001,2.10399122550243));
#625=CARTESIAN_POINT('',(7.4213072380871,3.50000000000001,2.29089501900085));
#626=CARTESIAN_POINT('',(7.56313135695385,3.50000000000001,2.35347033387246));
#627=CARTESIAN_POINT('',(7.84655848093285,3.50000000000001,2.47911718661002));
#628=CARTESIAN_POINT('',(7.98816148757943,3.50000000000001,2.54218872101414));
#629=CARTESIAN_POINT('',(8.12966958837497,3.5,2.60547239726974));
#630=B_SPLINE_CURVE_WITH_KNOTS('',3,(#576,#577,#578,#579,#580,#581,#582,#583,#584,#585,#586,
#587,#588,#589,#590,#591,#592,#593,#594,#595,#596,#597,#598,#599,#600,#601,#602,#603,#604,#605,
#606,#607,#608,#609,#610,#611,#612,#613,#614,#615,#616,#617,#618,#619,#620,#621,#622,#623,#624,
#625,#626,#627,#628,#629),.UNSPECIFIED.,.F.,.F.,(4,2,2,2,2,2,2,2,2,2,2,2,2,2,2,2,2,2,2,2,2,2,2,
2,2,2,4),(0.,0.508706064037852,1.01748184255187,1.52816774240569,2.03883407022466,
2.54268992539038,3.04657607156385,3.54988371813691,4.05310843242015,4.70913509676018,
5.03708789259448,5.3650028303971,5.69426569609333,6.02350358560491,6.35275431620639,
6.68199103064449,7.61182426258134,8.07745018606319,8.54304356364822,9.01174161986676,
9.48045909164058,10.4173206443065,11.3618979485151,12.3066183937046,13.2369432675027,
13.7019885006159,14.1670304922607),.UNSPECIFIED.);
#631=CARTESIAN_POINT('',(0.,3.5,0.));
#632=VERTEX_POINT('',#631);
#633=EDGE_CURVE('E307',#497,#632,#630,.F.);
#634=ORIENTED_EDGE('',*,*,#633,.T.);
#635=EDGE_CURVE('E312',#632,#66,#630,.F.);
#636=ORIENTED_EDGE('',*,*,#635,.T.);
#637=ORIENTED_EDGE('',*,*,#67,.F.);
#638=EDGE_LOOP('',(#572,#574,#575,#634,#636,#637));
#639=FACE_BOUND('',#638,.T.);
#640=ADVANCED_FACE('F326',(#639),#513,.F.);
#641=CARTESIAN_POINT('',(0.,0.,0.263636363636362));
#642=DIRECTION('',(0.,0.,1.));
#643=DIRECTION('',(1.,0.,0.));
#644=AXIS2_PLACEMENT_3D('',#641,#642,#643);
#645=CONICAL_SURFACE('',#644,4.04145188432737,1.11767839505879);
#646=CARTESIAN_POINT('',(0.,0.,0.));
#647=DIRECTION('',(0.,0.,1.));
#648=DIRECTION('',(1.,0.,0.));
#649=AXIS2_PLACEMENT_3D('',#646,#647,#648);
#650=CIRCLE('',#649,3.5);
#651=EDGE_CURVE('E243',#493,#408,#650,.F.);
#652=ORIENTED_EDGE('',*,*,#651,.F.);
#653=ORIENTED_EDGE('',*,*,#494,.F.);
#654=ORIENTED_EDGE('',*,*,#413,.F.);
#655=EDGE_LOOP('',(#652,#653,#654));
#656=FACE_BOUND('',#655,.T.);
#657=ADVANCED_FACE('F302',(#656),#645,.T.);
#658=EDGE_CURVE('E245',#632,#493,#650,.F.);
#659=ORIENTED_EDGE('',*,*,#658,.F.);
#660=ORIENTED_EDGE('',*,*,#633,.F.);
#661=ORIENTED_EDGE('',*,*,#498,.F.);
#662=EDGE_LOOP('',(#659,#660,#661));
#663=FACE_BOUND('',#662,.T.);
#664=ADVANCED_FACE('F366',(#663),#645,.T.);
#665=ORIENTED_EDGE('',*,*,#635,.F.);
#666=CARTESIAN_POINT('',(0.,0.,0.));
#667=DIRECTION('',(0.,0.,-1.));
#668=DIRECTION('',(-1.,0.,0.));
#669=AXIS2_PLACEMENT_3D('',#666,#667,#668);
#670=CIRCLE('',#669,3.5);
#671=EDGE_CURVE('E290',#97,#632,#670,.T.);
#672=ORIENTED_EDGE('',*,*,#671,.F.);
#673=ORIENTED_EDGE('',*,*,#98,.F.);
#674=EDGE_LOOP('',(#665,#672,#673));
#675=FACE_BOUND('',#674,.T.);
#676=ADVANCED_FACE('F178',(#675),#645,.T.);
#677=EDGE_CURVE('E272',#182,#97,#650,.F.);
#678=ORIENTED_EDGE('',*,*,#677,.F.);
#679=ORIENTED_EDGE('',*,*,#183,.F.);
#680=ORIENTED_EDGE('',*,*,#102,.F.);
#681=EDGE_LOOP('',(#678,#679,#680));
#682=FACE_BOUND('',#681,.T.);
#683=ADVANCED_FACE('F269',(#682),#645,.T.);
#684=EDGE_CURVE('E276',#323,#182,#650,.F.);
#685=ORIENTED_EDGE('',*,*,#684,.F.);
#686=ORIENTED_EDGE('',*,*,#324,.F.);
#687=ORIENTED_EDGE('',*,*,#187,.F.);
#688=EDGE_LOOP('',(#685,#686,#687));
#689=FACE_BOUND('',#688,.T.);
#690=ADVANCED_FACE('F282',(#689),#645,.T.);
#691=EDGE_CURVE('E54',#408,#323,#650,.F.);
#692=ORIENTED_EDGE('',*,*,#691,.F.);
#693=ORIENTED_EDGE('',*,*,#409,.F.);
#694=ORIENTED_EDGE('',*,*,#328,.F.);
#695=EDGE_LOOP('',(#692,#693,#694));
#696=FACE_BOUND('',#695,.T.);
#697=ADVANCED_FACE('F367',(#696),#645,.T.);
#698=CARTESIAN_POINT('',(-6.06217782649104,-3.5,0.));
#699=DIRECTION('',(0.,0.,1.));
#700=DIRECTION('',(1.,0.,0.));
#701=AXIS2_PLACEMENT_3D('',#698,#699,#700);
#702=PLANE('',#701);
#703=CARTESIAN_POINT('',(0.,0.,0.));
#704=DIRECTION('',(0.,0.,1.));
#705=DIRECTION('',(1.,0.,0.));
#706=AXIS2_PLACEMENT_3D('',#703,#704,#705);
#707=CIRCLE('',#706,2.);
#708=CARTESIAN_POINT('',(2.,0.,0.));
#709=VERTEX_POINT('',#708);
#710=EDGE_CURVE('E499',#709,#709,#707,.T.);
#711=ORIENTED_EDGE('',*,*,#710,.T.);
#712=EDGE_LOOP('',(#711));
#713=FACE_BOUND('',#712,.T.);
#714=ORIENTED_EDGE('',*,*,#651,.T.);
#715=ORIENTED_EDGE('',*,*,#691,.T.);
#716=ORIENTED_EDGE('',*,*,#684,.T.);
#717=ORIENTED_EDGE('',*,*,#677,.T.);
#718=ORIENTED_EDGE('',*,*,#671,.T.);
#719=ORIENTED_EDGE('',*,*,#658,.T.);
#720=EDGE_LOOP('',(#714,#715,#716,#717,#718,#719));
#721=FACE_BOUND('',#720,.T.);
#722=ADVANCED_FACE('F278',(#713,#721),#702,.F.);
#723=CARTESIAN_POINT('',(0.,0.,2.9));
#724=DIRECTION('',(0.,0.,-1.));
#725=DIRECTION('',(-1.,0.,0.));
#726=AXIS2_PLACEMENT_3D('',#723,#724,#725);
#727=CONICAL_SURFACE('',#726,3.5,1.11767839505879);
#728=ORIENTED_EDGE('',*,*,#462,.F.);
#729=CARTESIAN_POINT('',(0.,0.,2.9));
#730=DIRECTION('',(0.,0.,1.));
#731=DIRECTION('',(1.,0.,0.));
#732=AXIS2_PLACEMENT_3D('',#729,#730,#731);
#733=CIRCLE('',#732,3.5);
#734=EDGE_CURVE('E122',#459,#374,#733,.F.);
#735=ORIENTED_EDGE('',*,*,#734,.T.);
#736=ORIENTED_EDGE('',*,*,#375,.F.);
#737=EDGE_LOOP('',(#728,#735,#736));
#738=FACE_BOUND('',#737,.T.);
#739=ADVANCED_FACE('F138',(#738),#727,.T.);
#740=ORIENTED_EDGE('',*,*,#573,.F.);
#741=EDGE_CURVE('E124',#570,#459,#733,.F.);
#742=ORIENTED_EDGE('',*,*,#741,.T.);
#743=ORIENTED_EDGE('',*,*,#460,.F.);
#744=EDGE_LOOP('',(#740,#742,#743));
#745=FACE_BOUND('',#744,.T.);
#746=ADVANCED_FACE('F132',(#745),#727,.T.);
#747=CARTESIAN_POINT('',(0.,0.,2.9));
#748=DIRECTION('',(0.,0.,-1.));
#749=DIRECTION('',(-1.,0.,0.));
#750=AXIS2_PLACEMENT_3D('',#747,#748,#749);
#751=CIRCLE('',#750,3.5);
#752=EDGE_CURVE('E501',#54,#570,#751,.T.);
#753=ORIENTED_EDGE('',*,*,#752,.T.);
#754=ORIENTED_EDGE('',*,*,#571,.F.);
#755=ORIENTED_EDGE('',*,*,#59,.F.);
#756=EDGE_LOOP('',(#753,#754,#755));
#757=FACE_BOUND('',#756,.T.);
#758=ADVANCED_FACE('F419',(#757),#727,.T.);
#759=EDGE_CURVE('E135',#148,#54,#733,.F.);
#760=ORIENTED_EDGE('',*,*,#759,.T.);
#761=ORIENTED_EDGE('',*,*,#55,.F.);
#762=ORIENTED_EDGE('',*,*,#151,.F.);
#763=EDGE_LOOP('',(#760,#761,#762));
#764=FACE_BOUND('',#763,.T.);
#765=ADVANCED_FACE('F259',(#764),#727,.T.);
#766=EDGE_CURVE('E249',#261,#148,#733,.F.);
#767=ORIENTED_EDGE('',*,*,#766,.T.);
#768=ORIENTED_EDGE('',*,*,#149,.F.);
#769=ORIENTED_EDGE('',*,*,#264,.F.);
#770=EDGE_LOOP('',(#767,#768,#769));
#771=FACE_BOUND('',#770,.T.);
#772=ADVANCED_FACE('F175',(#771),#727,.T.);
#773=ORIENTED_EDGE('',*,*,#377,.F.);
#774=EDGE_CURVE('E126',#374,#261,#733,.F.);
#775=ORIENTED_EDGE('',*,*,#774,.T.);
#776=ORIENTED_EDGE('',*,*,#262,.F.);
#777=EDGE_LOOP('',(#773,#775,#776));
#778=FACE_BOUND('',#777,.T.);
#779=ADVANCED_FACE('F170',(#778),#727,.T.);
#780=CARTESIAN_POINT('',(0.,0.,6.));
#781=DIRECTION('',(0.,0.,-1.));
#782=DIRECTION('',(-1.,0.,0.));
#783=AXIS2_PLACEMENT_3D('',#780,#781,#782);
#784=CYLINDRICAL_SURFACE('',#783,3.5);
#785=CARTESIAN_POINT('',(0.,0.,5.31951666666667));
#786=DIRECTION('',(0.,0.,-1.));
#787=DIRECTION('',(-1.,0.,0.));
#788=AXIS2_PLACEMENT_3D('',#785,#786,#787);
#789=CIRCLE('',#788,3.5);
#790=CARTESIAN_POINT('',(-3.50000000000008,0.,5.31951666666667));
#791=VERTEX_POINT('',#790);
#792=EDGE_CURVE('E39',#791,#791,#789,.T.);
#793=ORIENTED_EDGE('',*,*,#792,.T.);
#794=EDGE_LOOP('',(#793));
#795=FACE_BOUND('',#794,.T.);
#796=ORIENTED_EDGE('',*,*,#734,.F.);
#797=ORIENTED_EDGE('',*,*,#741,.F.);
#798=ORIENTED_EDGE('',*,*,#752,.F.);
#799=ORIENTED_EDGE('',*,*,#759,.F.);
#800=ORIENTED_EDGE('',*,*,#766,.F.);
#801=ORIENTED_EDGE('',*,*,#774,.F.);
#802=EDGE_LOOP('',(#796,#797,#798,#799,#800,#801));
#803=FACE_BOUND('',#802,.T.);
#804=ADVANCED_FACE('F123',(#795,#803),#784,.T.);
#805=CARTESIAN_POINT('',(0.,0.,6.));
#806=DIRECTION('',(0.,0.,-1.));
#807=DIRECTION('',(-1.,0.,0.));
#808=AXIS2_PLACEMENT_3D('',#805,#806,#807);
#809=PLANE('',#808);
#810=CARTESIAN_POINT('',(0.,0.,6.));
#811=DIRECTION('',(0.,0.,1.));
#812=DIRECTION('',(1.,0.,0.));
#813=AXIS2_PLACEMENT_3D('',#810,#811,#812);
#814=CIRCLE('',#813,2.);
#815=CARTESIAN_POINT('',(2.,0.,6.));
#816=VERTEX_POINT('',#815);
#817=EDGE_CURVE('E496',#816,#816,#814,.T.);
#818=ORIENTED_EDGE('',*,*,#817,.F.);
#819=EDGE_LOOP('',(#818));
#820=FACE_BOUND('',#819,.T.);
#821=CARTESIAN_POINT('',(0.,0.,6.));
#822=DIRECTION('',(0.,0.,-1.));
#823=DIRECTION('',(-1.,0.,0.));
#824=AXIS2_PLACEMENT_3D('',#821,#822,#823);
#825=CIRCLE('',#824,2.81951666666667);
#826=CARTESIAN_POINT('',(-2.81951666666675,0.,6.));
#827=VERTEX_POINT('',#826);
#828=EDGE_CURVE('E11',#827,#827,#825,.F.);
#829=ORIENTED_EDGE('',*,*,#828,.T.);
#830=EDGE_LOOP('',(#829));
#831=FACE_BOUND('',#830,.T.);
#832=ADVANCED_FACE('F462',(#820,#831),#809,.F.);
#833=CARTESIAN_POINT('',(0.,0.,5.31951666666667));
#834=DIRECTION('',(0.,0.,-1.));
#835=DIRECTION('',(-1.,0.,0.));
#836=AXIS2_PLACEMENT_3D('',#833,#834,#835);
#837=TOROIDAL_SURFACE('',#836,2.81951666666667,0.680483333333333);
#838=ORIENTED_EDGE('',*,*,#828,.F.);
#839=EDGE_LOOP('',(#838));
#840=FACE_BOUND('',#839,.T.);
#841=ORIENTED_EDGE('',*,*,#792,.F.);
#842=EDGE_LOOP('',(#841));
#843=FACE_BOUND('',#842,.T.);
#844=ADVANCED_FACE('F470',(#840,#843),#837,.T.);
#845=CARTESIAN_POINT('',(0.,0.,6.));
#846=DIRECTION('',(0.,0.,-1.));
#847=DIRECTION('',(-1.,0.,0.));
#848=AXIS2_PLACEMENT_3D('',#845,#846,#847);
#849=CYLINDRICAL_SURFACE('',#848,2.);
#850=ORIENTED_EDGE('',*,*,#817,.T.);
#851=EDGE_LOOP('',(#850));
#852=FACE_BOUND('',#851,.T.);
#853=ORIENTED_EDGE('',*,*,#710,.F.);
#854=EDGE_LOOP('',(#853));
#855=FACE_BOUND('',#854,.T.);
#856=ADVANCED_FACE('F479',(#852,#855),#849,.F.);
#857=CLOSED_SHELL('',(#112,#197,#338,#423,#508,#640,#657,#664,#676,#683,#690,#697,#722,#739,
#746,#758,#765,#772,#779,#804,#832,#844,#856));
#858=MANIFOLD_SOLID_BREP('B2',#857);
#859=ADVANCED_BREP_SHAPE_REPRESENTATION('',(#18,#858),#14);
#860=SHAPE_DEFINITION_REPRESENTATION(#9,#859);
ENDSEC;
END-ISO-10303-21;
